# Generated deterministically by seda-macro-lef-normalizer-v1; recipe orfs-ng45-fakeram-metal3-coupledl2-pg-v1.
VERSION 5.8 ;
BUSBITCHARS "[]" ;
DIVIDERCHAR "/" ;

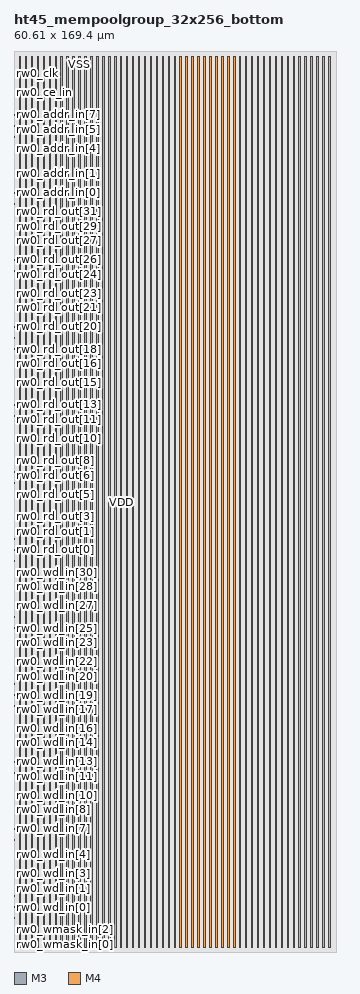
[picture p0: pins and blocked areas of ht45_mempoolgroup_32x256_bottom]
MACRO ht45_mempoolgroup_32x256_bottom
  FOREIGN ht45_mempoolgroup_32x256_bottom 0 0 ;
  CLASS COVER ;
  ORIGIN 0 0 ;
  SIZE 60.61 BY 169.4 ;
  SYMMETRY X Y R90 ;
  PIN rw0_wmask_in[0]
    DIRECTION INPUT ;
    USE SIGNAL ;
    SHAPE ABUTMENT ;
    PORT
      LAYER M3 ;
      RECT 0 0.035 0.07 0.105 ;
    END
  END rw0_wmask_in[0]
  PIN rw0_wmask_in[1]
    DIRECTION INPUT ;
    USE SIGNAL ;
    SHAPE ABUTMENT ;
    PORT
      LAYER M3 ;
      RECT 0 2.135 0.07 2.205 ;
    END
  END rw0_wmask_in[1]
  PIN rw0_wmask_in[2]
    DIRECTION INPUT ;
    USE SIGNAL ;
    SHAPE ABUTMENT ;
    PORT
      LAYER M3 ;
      RECT 0 4.235 0.07 4.305 ;
    END
  END rw0_wmask_in[2]
  PIN rw0_wmask_in[3]
    DIRECTION INPUT ;
    USE SIGNAL ;
    SHAPE ABUTMENT ;
    PORT
      LAYER M3 ;
      RECT 0 6.335 0.07 6.405 ;
    END
  END rw0_wmask_in[3]
  PIN rw0_wd_in[0]
    DIRECTION INPUT ;
    USE SIGNAL ;
    SHAPE ABUTMENT ;
    PORT
      LAYER M3 ;
      RECT 0 8.435 0.07 8.505 ;
    END
  END rw0_wd_in[0]
  PIN rw0_wd_in[1]
    DIRECTION INPUT ;
    USE SIGNAL ;
    SHAPE ABUTMENT ;
    PORT
      LAYER M3 ;
      RECT 0 10.535 0.07 10.605 ;
    END
  END rw0_wd_in[1]
  PIN rw0_wd_in[2]
    DIRECTION INPUT ;
    USE SIGNAL ;
    SHAPE ABUTMENT ;
    PORT
      LAYER M3 ;
      RECT 0 12.635 0.07 12.705 ;
    END
  END rw0_wd_in[2]
  PIN rw0_wd_in[3]
    DIRECTION INPUT ;
    USE SIGNAL ;
    SHAPE ABUTMENT ;
    PORT
      LAYER M3 ;
      RECT 0 14.735 0.07 14.805 ;
    END
  END rw0_wd_in[3]
  PIN rw0_wd_in[4]
    DIRECTION INPUT ;
    USE SIGNAL ;
    SHAPE ABUTMENT ;
    PORT
      LAYER M3 ;
      RECT 0 16.835 0.07 16.905 ;
    END
  END rw0_wd_in[4]
  PIN rw0_wd_in[5]
    DIRECTION INPUT ;
    USE SIGNAL ;
    SHAPE ABUTMENT ;
    PORT
      LAYER M3 ;
      RECT 0 18.935 0.07 19.005 ;
    END
  END rw0_wd_in[5]
  PIN rw0_wd_in[6]
    DIRECTION INPUT ;
    USE SIGNAL ;
    SHAPE ABUTMENT ;
    PORT
      LAYER M3 ;
      RECT 0 21.035 0.07 21.105 ;
    END
  END rw0_wd_in[6]
  PIN rw0_wd_in[7]
    DIRECTION INPUT ;
    USE SIGNAL ;
    SHAPE ABUTMENT ;
    PORT
      LAYER M3 ;
      RECT 0 23.135 0.07 23.205 ;
    END
  END rw0_wd_in[7]
  PIN rw0_wd_in[8]
    DIRECTION INPUT ;
    USE SIGNAL ;
    SHAPE ABUTMENT ;
    PORT
      LAYER M3 ;
      RECT 0 25.235 0.07 25.305 ;
    END
  END rw0_wd_in[8]
  PIN rw0_wd_in[9]
    DIRECTION INPUT ;
    USE SIGNAL ;
    SHAPE ABUTMENT ;
    PORT
      LAYER M3 ;
      RECT 0 27.335 0.07 27.405 ;
    END
  END rw0_wd_in[9]
  PIN rw0_wd_in[10]
    DIRECTION INPUT ;
    USE SIGNAL ;
    SHAPE ABUTMENT ;
    PORT
      LAYER M3 ;
      RECT 0 29.435 0.07 29.505 ;
    END
  END rw0_wd_in[10]
  PIN rw0_wd_in[11]
    DIRECTION INPUT ;
    USE SIGNAL ;
    SHAPE ABUTMENT ;
    PORT
      LAYER M3 ;
      RECT 0 31.535 0.07 31.605 ;
    END
  END rw0_wd_in[11]
  PIN rw0_wd_in[12]
    DIRECTION INPUT ;
    USE SIGNAL ;
    SHAPE ABUTMENT ;
    PORT
      LAYER M3 ;
      RECT 0 33.635 0.07 33.705 ;
    END
  END rw0_wd_in[12]
  PIN rw0_wd_in[13]
    DIRECTION INPUT ;
    USE SIGNAL ;
    SHAPE ABUTMENT ;
    PORT
      LAYER M3 ;
      RECT 0 35.735 0.07 35.805 ;
    END
  END rw0_wd_in[13]
  PIN rw0_wd_in[14]
    DIRECTION INPUT ;
    USE SIGNAL ;
    SHAPE ABUTMENT ;
    PORT
      LAYER M3 ;
      RECT 0 37.835 0.07 37.905 ;
    END
  END rw0_wd_in[14]
  PIN rw0_wd_in[15]
    DIRECTION INPUT ;
    USE SIGNAL ;
    SHAPE ABUTMENT ;
    PORT
      LAYER M3 ;
      RECT 0 39.935 0.07 40.005 ;
    END
  END rw0_wd_in[15]
  PIN rw0_wd_in[16]
    DIRECTION INPUT ;
    USE SIGNAL ;
    SHAPE ABUTMENT ;
    PORT
      LAYER M3 ;
      RECT 0 42.035 0.07 42.105 ;
    END
  END rw0_wd_in[16]
  PIN rw0_wd_in[17]
    DIRECTION INPUT ;
    USE SIGNAL ;
    SHAPE ABUTMENT ;
    PORT
      LAYER M3 ;
      RECT 0 44.135 0.07 44.205 ;
    END
  END rw0_wd_in[17]
  PIN rw0_wd_in[18]
    DIRECTION INPUT ;
    USE SIGNAL ;
    SHAPE ABUTMENT ;
    PORT
      LAYER M3 ;
      RECT 0 46.235 0.07 46.305 ;
    END
  END rw0_wd_in[18]
  PIN rw0_wd_in[19]
    DIRECTION INPUT ;
    USE SIGNAL ;
    SHAPE ABUTMENT ;
    PORT
      LAYER M3 ;
      RECT 0 48.335 0.07 48.405 ;
    END
  END rw0_wd_in[19]
  PIN rw0_wd_in[20]
    DIRECTION INPUT ;
    USE SIGNAL ;
    SHAPE ABUTMENT ;
    PORT
      LAYER M3 ;
      RECT 0 50.435 0.07 50.505 ;
    END
  END rw0_wd_in[20]
  PIN rw0_wd_in[21]
    DIRECTION INPUT ;
    USE SIGNAL ;
    SHAPE ABUTMENT ;
    PORT
      LAYER M3 ;
      RECT 0 52.535 0.07 52.605 ;
    END
  END rw0_wd_in[21]
  PIN rw0_wd_in[22]
    DIRECTION INPUT ;
    USE SIGNAL ;
    SHAPE ABUTMENT ;
    PORT
      LAYER M3 ;
      RECT 0 54.635 0.07 54.705 ;
    END
  END rw0_wd_in[22]
  PIN rw0_wd_in[23]
    DIRECTION INPUT ;
    USE SIGNAL ;
    SHAPE ABUTMENT ;
    PORT
      LAYER M3 ;
      RECT 0 56.735 0.07 56.805 ;
    END
  END rw0_wd_in[23]
  PIN rw0_wd_in[24]
    DIRECTION INPUT ;
    USE SIGNAL ;
    SHAPE ABUTMENT ;
    PORT
      LAYER M3 ;
      RECT 0 58.835 0.07 58.905 ;
    END
  END rw0_wd_in[24]
  PIN rw0_wd_in[25]
    DIRECTION INPUT ;
    USE SIGNAL ;
    SHAPE ABUTMENT ;
    PORT
      LAYER M3 ;
      RECT 0 60.935 0.07 61.005 ;
    END
  END rw0_wd_in[25]
  PIN rw0_wd_in[26]
    DIRECTION INPUT ;
    USE SIGNAL ;
    SHAPE ABUTMENT ;
    PORT
      LAYER M3 ;
      RECT 0 63.035 0.07 63.105 ;
    END
  END rw0_wd_in[26]
  PIN rw0_wd_in[27]
    DIRECTION INPUT ;
    USE SIGNAL ;
    SHAPE ABUTMENT ;
    PORT
      LAYER M3 ;
      RECT 0 65.135 0.07 65.205 ;
    END
  END rw0_wd_in[27]
  PIN rw0_wd_in[28]
    DIRECTION INPUT ;
    USE SIGNAL ;
    SHAPE ABUTMENT ;
    PORT
      LAYER M3 ;
      RECT 0 67.235 0.07 67.305 ;
    END
  END rw0_wd_in[28]
  PIN rw0_wd_in[29]
    DIRECTION INPUT ;
    USE SIGNAL ;
    SHAPE ABUTMENT ;
    PORT
      LAYER M3 ;
      RECT 0 69.335 0.07 69.405 ;
    END
  END rw0_wd_in[29]
  PIN rw0_wd_in[30]
    DIRECTION INPUT ;
    USE SIGNAL ;
    SHAPE ABUTMENT ;
    PORT
      LAYER M3 ;
      RECT 0 71.435 0.07 71.505 ;
    END
  END rw0_wd_in[30]
  PIN rw0_wd_in[31]
    DIRECTION INPUT ;
    USE SIGNAL ;
    SHAPE ABUTMENT ;
    PORT
      LAYER M3 ;
      RECT 0 73.535 0.07 73.605 ;
    END
  END rw0_wd_in[31]
  PIN rw0_rd_out[0]
    DIRECTION OUTPUT ;
    USE SIGNAL ;
    SHAPE ABUTMENT ;
    PORT
      LAYER M3 ;
      RECT 0 75.635 0.07 75.705 ;
    END
  END rw0_rd_out[0]
  PIN rw0_rd_out[1]
    DIRECTION OUTPUT ;
    USE SIGNAL ;
    SHAPE ABUTMENT ;
    PORT
      LAYER M3 ;
      RECT 0 77.735 0.07 77.805 ;
    END
  END rw0_rd_out[1]
  PIN rw0_rd_out[2]
    DIRECTION OUTPUT ;
    USE SIGNAL ;
    SHAPE ABUTMENT ;
    PORT
      LAYER M3 ;
      RECT 0 79.835 0.07 79.905 ;
    END
  END rw0_rd_out[2]
  PIN rw0_rd_out[3]
    DIRECTION OUTPUT ;
    USE SIGNAL ;
    SHAPE ABUTMENT ;
    PORT
      LAYER M3 ;
      RECT 0 81.935 0.07 82.005 ;
    END
  END rw0_rd_out[3]
  PIN rw0_rd_out[4]
    DIRECTION OUTPUT ;
    USE SIGNAL ;
    SHAPE ABUTMENT ;
    PORT
      LAYER M3 ;
      RECT 0 84.035 0.07 84.105 ;
    END
  END rw0_rd_out[4]
  PIN rw0_rd_out[5]
    DIRECTION OUTPUT ;
    USE SIGNAL ;
    SHAPE ABUTMENT ;
    PORT
      LAYER M3 ;
      RECT 0 86.135 0.07 86.205 ;
    END
  END rw0_rd_out[5]
  PIN rw0_rd_out[6]
    DIRECTION OUTPUT ;
    USE SIGNAL ;
    SHAPE ABUTMENT ;
    PORT
      LAYER M3 ;
      RECT 0 88.235 0.07 88.305 ;
    END
  END rw0_rd_out[6]
  PIN rw0_rd_out[7]
    DIRECTION OUTPUT ;
    USE SIGNAL ;
    SHAPE ABUTMENT ;
    PORT
      LAYER M3 ;
      RECT 0 90.335 0.07 90.405 ;
    END
  END rw0_rd_out[7]
  PIN rw0_rd_out[8]
    DIRECTION OUTPUT ;
    USE SIGNAL ;
    SHAPE ABUTMENT ;
    PORT
      LAYER M3 ;
      RECT 0 92.435 0.07 92.505 ;
    END
  END rw0_rd_out[8]
  PIN rw0_rd_out[9]
    DIRECTION OUTPUT ;
    USE SIGNAL ;
    SHAPE ABUTMENT ;
    PORT
      LAYER M3 ;
      RECT 0 94.535 0.07 94.605 ;
    END
  END rw0_rd_out[9]
  PIN rw0_rd_out[10]
    DIRECTION OUTPUT ;
    USE SIGNAL ;
    SHAPE ABUTMENT ;
    PORT
      LAYER M3 ;
      RECT 0 96.635 0.07 96.705 ;
    END
  END rw0_rd_out[10]
  PIN rw0_rd_out[11]
    DIRECTION OUTPUT ;
    USE SIGNAL ;
    SHAPE ABUTMENT ;
    PORT
      LAYER M3 ;
      RECT 0 98.735 0.07 98.805 ;
    END
  END rw0_rd_out[11]
  PIN rw0_rd_out[12]
    DIRECTION OUTPUT ;
    USE SIGNAL ;
    SHAPE ABUTMENT ;
    PORT
      LAYER M3 ;
      RECT 0 100.835 0.07 100.905 ;
    END
  END rw0_rd_out[12]
  PIN rw0_rd_out[13]
    DIRECTION OUTPUT ;
    USE SIGNAL ;
    SHAPE ABUTMENT ;
    PORT
      LAYER M3 ;
      RECT 0 102.935 0.07 103.005 ;
    END
  END rw0_rd_out[13]
  PIN rw0_rd_out[14]
    DIRECTION OUTPUT ;
    USE SIGNAL ;
    SHAPE ABUTMENT ;
    PORT
      LAYER M3 ;
      RECT 0 105.035 0.07 105.105 ;
    END
  END rw0_rd_out[14]
  PIN rw0_rd_out[15]
    DIRECTION OUTPUT ;
    USE SIGNAL ;
    SHAPE ABUTMENT ;
    PORT
      LAYER M3 ;
      RECT 0 107.135 0.07 107.205 ;
    END
  END rw0_rd_out[15]
  PIN rw0_rd_out[16]
    DIRECTION OUTPUT ;
    USE SIGNAL ;
    SHAPE ABUTMENT ;
    PORT
      LAYER M3 ;
      RECT 0 109.235 0.07 109.305 ;
    END
  END rw0_rd_out[16]
  PIN rw0_rd_out[17]
    DIRECTION OUTPUT ;
    USE SIGNAL ;
    SHAPE ABUTMENT ;
    PORT
      LAYER M3 ;
      RECT 0 111.335 0.07 111.405 ;
    END
  END rw0_rd_out[17]
  PIN rw0_rd_out[18]
    DIRECTION OUTPUT ;
    USE SIGNAL ;
    SHAPE ABUTMENT ;
    PORT
      LAYER M3 ;
      RECT 0 113.435 0.07 113.505 ;
    END
  END rw0_rd_out[18]
  PIN rw0_rd_out[19]
    DIRECTION OUTPUT ;
    USE SIGNAL ;
    SHAPE ABUTMENT ;
    PORT
      LAYER M3 ;
      RECT 0 115.535 0.07 115.605 ;
    END
  END rw0_rd_out[19]
  PIN rw0_rd_out[20]
    DIRECTION OUTPUT ;
    USE SIGNAL ;
    SHAPE ABUTMENT ;
    PORT
      LAYER M3 ;
      RECT 0 117.635 0.07 117.705 ;
    END
  END rw0_rd_out[20]
  PIN rw0_rd_out[21]
    DIRECTION OUTPUT ;
    USE SIGNAL ;
    SHAPE ABUTMENT ;
    PORT
      LAYER M3 ;
      RECT 0 119.735 0.07 119.805 ;
    END
  END rw0_rd_out[21]
  PIN rw0_rd_out[22]
    DIRECTION OUTPUT ;
    USE SIGNAL ;
    SHAPE ABUTMENT ;
    PORT
      LAYER M3 ;
      RECT 0 121.835 0.07 121.905 ;
    END
  END rw0_rd_out[22]
  PIN rw0_rd_out[23]
    DIRECTION OUTPUT ;
    USE SIGNAL ;
    SHAPE ABUTMENT ;
    PORT
      LAYER M3 ;
      RECT 0 123.935 0.07 124.005 ;
    END
  END rw0_rd_out[23]
  PIN rw0_rd_out[24]
    DIRECTION OUTPUT ;
    USE SIGNAL ;
    SHAPE ABUTMENT ;
    PORT
      LAYER M3 ;
      RECT 0 126.035 0.07 126.105 ;
    END
  END rw0_rd_out[24]
  PIN rw0_rd_out[25]
    DIRECTION OUTPUT ;
    USE SIGNAL ;
    SHAPE ABUTMENT ;
    PORT
      LAYER M3 ;
      RECT 0 128.135 0.07 128.205 ;
    END
  END rw0_rd_out[25]
  PIN rw0_rd_out[26]
    DIRECTION OUTPUT ;
    USE SIGNAL ;
    SHAPE ABUTMENT ;
    PORT
      LAYER M3 ;
      RECT 0 130.235 0.07 130.305 ;
    END
  END rw0_rd_out[26]
  PIN rw0_rd_out[27]
    DIRECTION OUTPUT ;
    USE SIGNAL ;
    SHAPE ABUTMENT ;
    PORT
      LAYER M3 ;
      RECT 0 132.335 0.07 132.405 ;
    END
  END rw0_rd_out[27]
  PIN rw0_rd_out[28]
    DIRECTION OUTPUT ;
    USE SIGNAL ;
    SHAPE ABUTMENT ;
    PORT
      LAYER M3 ;
      RECT 0 134.435 0.07 134.505 ;
    END
  END rw0_rd_out[28]
  PIN rw0_rd_out[29]
    DIRECTION OUTPUT ;
    USE SIGNAL ;
    SHAPE ABUTMENT ;
    PORT
      LAYER M3 ;
      RECT 0 136.535 0.07 136.605 ;
    END
  END rw0_rd_out[29]
  PIN rw0_rd_out[30]
    DIRECTION OUTPUT ;
    USE SIGNAL ;
    SHAPE ABUTMENT ;
    PORT
      LAYER M3 ;
      RECT 0 138.635 0.07 138.705 ;
    END
  END rw0_rd_out[30]
  PIN rw0_rd_out[31]
    DIRECTION OUTPUT ;
    USE SIGNAL ;
    SHAPE ABUTMENT ;
    PORT
      LAYER M3 ;
      RECT 0 140.735 0.07 140.805 ;
    END
  END rw0_rd_out[31]
  PIN rw0_addr_in[0]
    DIRECTION INPUT ;
    USE SIGNAL ;
    SHAPE ABUTMENT ;
    PORT
      LAYER M3 ;
      RECT 0 142.835 0.07 142.905 ;
    END
  END rw0_addr_in[0]
  PIN rw0_addr_in[1]
    DIRECTION INPUT ;
    USE SIGNAL ;
    SHAPE ABUTMENT ;
    PORT
      LAYER M3 ;
      RECT 0 144.935 0.07 145.005 ;
    END
  END rw0_addr_in[1]
  PIN rw0_addr_in[2]
    DIRECTION INPUT ;
    USE SIGNAL ;
    SHAPE ABUTMENT ;
    PORT
      LAYER M3 ;
      RECT 0 147.035 0.07 147.105 ;
    END
  END rw0_addr_in[2]
  PIN rw0_addr_in[3]
    DIRECTION INPUT ;
    USE SIGNAL ;
    SHAPE ABUTMENT ;
    PORT
      LAYER M3 ;
      RECT 0 149.135 0.07 149.205 ;
    END
  END rw0_addr_in[3]
  PIN rw0_addr_in[4]
    DIRECTION INPUT ;
    USE SIGNAL ;
    SHAPE ABUTMENT ;
    PORT
      LAYER M3 ;
      RECT 0 151.235 0.07 151.305 ;
    END
  END rw0_addr_in[4]
  PIN rw0_addr_in[5]
    DIRECTION INPUT ;
    USE SIGNAL ;
    SHAPE ABUTMENT ;
    PORT
      LAYER M3 ;
      RECT 0 153.335 0.07 153.405 ;
    END
  END rw0_addr_in[5]
  PIN rw0_addr_in[6]
    DIRECTION INPUT ;
    USE SIGNAL ;
    SHAPE ABUTMENT ;
    PORT
      LAYER M3 ;
      RECT 0 155.435 0.07 155.505 ;
    END
  END rw0_addr_in[6]
  PIN rw0_addr_in[7]
    DIRECTION INPUT ;
    USE SIGNAL ;
    SHAPE ABUTMENT ;
    PORT
      LAYER M3 ;
      RECT 0 157.535 0.07 157.605 ;
    END
  END rw0_addr_in[7]
  PIN rw0_we_in
    DIRECTION INPUT ;
    USE SIGNAL ;
    SHAPE ABUTMENT ;
    PORT
      LAYER M3 ;
      RECT 0 159.635 0.07 159.705 ;
    END
  END rw0_we_in
  PIN rw0_ce_in
    DIRECTION INPUT ;
    USE SIGNAL ;
    SHAPE ABUTMENT ;
    PORT
      LAYER M3 ;
      RECT 0 161.735 0.07 161.805 ;
    END
  END rw0_ce_in
  PIN rw0_clk
    DIRECTION INPUT ;
    USE SIGNAL ;
    SHAPE ABUTMENT ;
    PORT
      LAYER M3 ;
      RECT 0 163.835 0.07 163.905 ;
    END
  END rw0_clk
  PIN VSS
    DIRECTION INOUT ;
    USE GROUND ;
    PORT
      LAYER M4 ;
      RECT 1 0.84 1.28 168.56 ;
      RECT 3.24 0.84 3.52 168.56 ;
      RECT 5.48 0.84 5.76 168.56 ;
      RECT 7.72 0.84 8 168.56 ;
      RECT 9.96 0.84 10.24 168.56 ;
      RECT 12.2 0.84 12.48 168.56 ;
      RECT 14.44 0.84 14.72 168.56 ;
      RECT 16.68 0.84 16.96 168.56 ;
      RECT 18.92 0.84 19.2 168.56 ;
      RECT 21.16 0.84 21.44 168.56 ;
      RECT 23.4 0.84 23.68 168.56 ;
      RECT 25.64 0.84 25.92 168.56 ;
      RECT 27.88 0.84 28.16 168.56 ;
      RECT 30.12 0.84 30.4 168.56 ;
      RECT 32.36 0.84 32.64 168.56 ;
      RECT 34.6 0.84 34.88 168.56 ;
      RECT 36.84 0.84 37.12 168.56 ;
      RECT 39.08 0.84 39.36 168.56 ;
      RECT 41.32 0.84 41.6 168.56 ;
      RECT 43.56 0.84 43.84 168.56 ;
      RECT 45.8 0.84 46.08 168.56 ;
      RECT 48.04 0.84 48.32 168.56 ;
      RECT 50.28 0.84 50.56 168.56 ;
      RECT 52.52 0.84 52.8 168.56 ;
      RECT 54.76 0.84 55.04 168.56 ;
      RECT 57 0.84 57.28 168.56 ;
      RECT 59.24 0.84 59.52 168.56 ;
    END
  END VSS
  PIN VDD
    DIRECTION INOUT ;
    USE POWER ;
    PORT
      LAYER M4 ;
      RECT 2.12 0.84 2.4 168.56 ;
      RECT 4.36 0.84 4.64 168.56 ;
      RECT 6.6 0.84 6.88 168.56 ;
      RECT 8.84 0.84 9.12 168.56 ;
      RECT 11.08 0.84 11.36 168.56 ;
      RECT 13.32 0.84 13.6 168.56 ;
      RECT 15.56 0.84 15.84 168.56 ;
      RECT 17.8 0.84 18.08 168.56 ;
      RECT 20.04 0.84 20.32 168.56 ;
      RECT 22.28 0.84 22.56 168.56 ;
      RECT 24.52 0.84 24.8 168.56 ;
      RECT 26.76 0.84 27.04 168.56 ;
      RECT 29 0.84 29.28 168.56 ;
      RECT 31.24 0.84 31.52 168.56 ;
      RECT 33.48 0.84 33.76 168.56 ;
      RECT 35.72 0.84 36 168.56 ;
      RECT 37.96 0.84 38.24 168.56 ;
      RECT 40.2 0.84 40.48 168.56 ;
      RECT 42.44 0.84 42.72 168.56 ;
      RECT 44.68 0.84 44.96 168.56 ;
      RECT 46.92 0.84 47.2 168.56 ;
      RECT 49.16 0.84 49.44 168.56 ;
      RECT 51.4 0.84 51.68 168.56 ;
      RECT 53.64 0.84 53.92 168.56 ;
      RECT 55.88 0.84 56.16 168.56 ;
      RECT 58.12 0.84 58.4 168.56 ;
    END
  END VDD
  OBS
    LAYER M1 ;
    RECT 0 0 60.61 169.4 ;
    LAYER M2 ;
    RECT 0 0 60.61 169.4 ;
  END
END ht45_mempoolgroup_32x256_bottom

END LIBRARY
